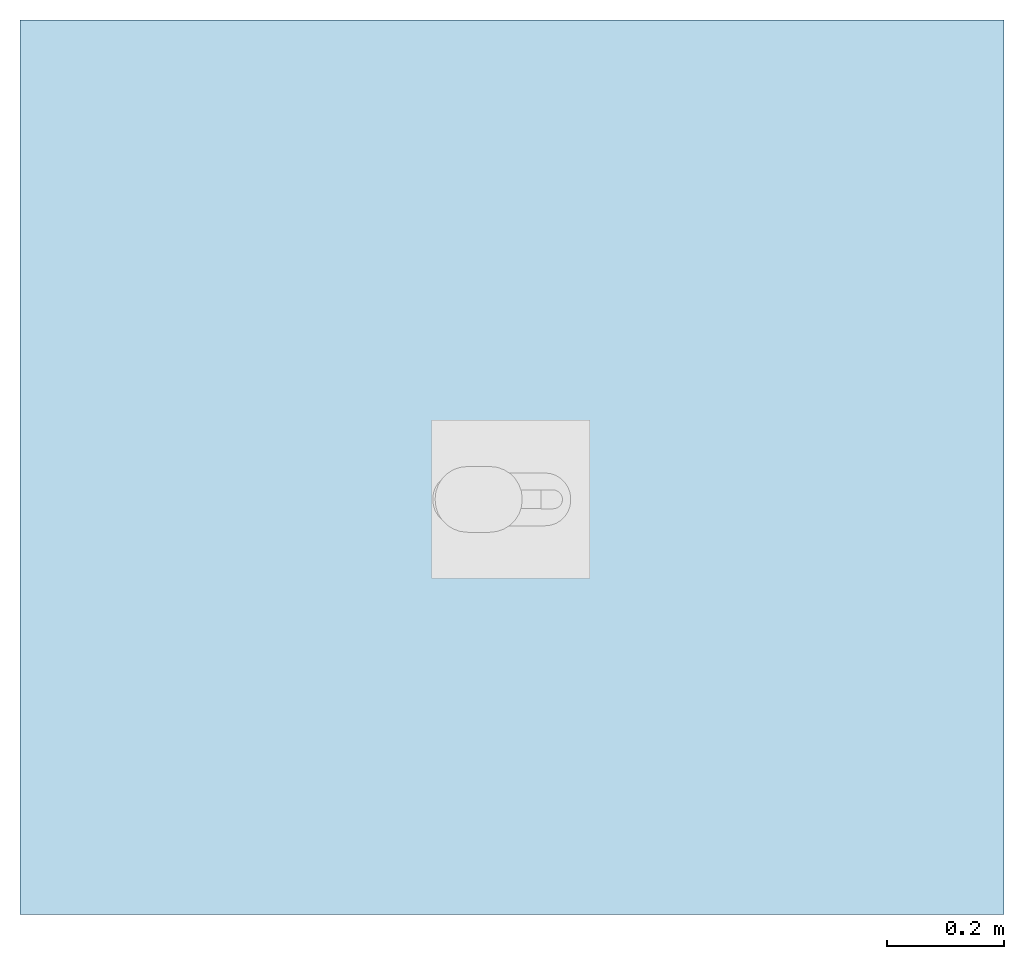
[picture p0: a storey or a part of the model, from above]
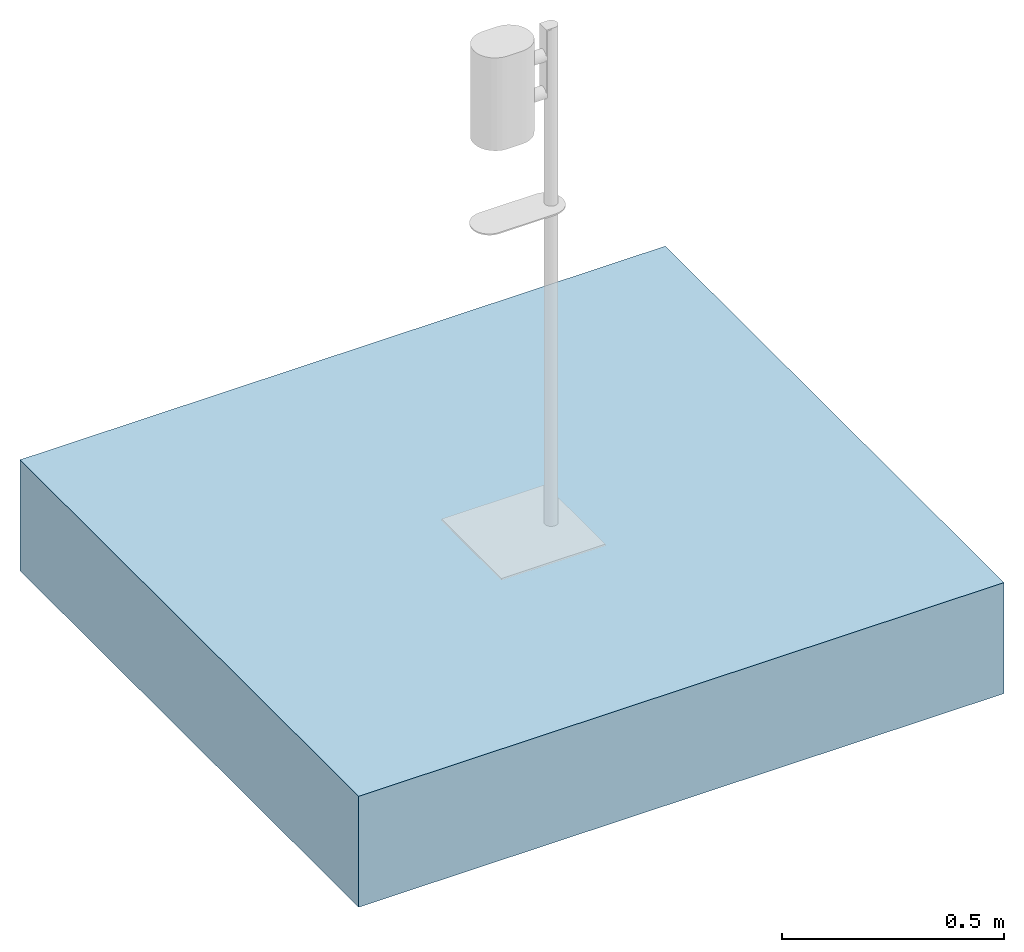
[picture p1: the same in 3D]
Properties of the parts of a building model (IFC2X3)

# File
Description: ViewDefinition [CoordinationView_V2.0]
File name: Project Number
Time: 2023-10-10T10:04:15
Written by: The EXPRESS Data Manager Version 5.02.0100.07 : 28 Aug 2013
Made in: 22.0.2.392 - Exporter 22.0.2.392 - Alternate UI 22.0.2.392
Comment: STEP Physical File produced by: The EXPRESS Data Manager Version 5.02.0100.07 : 28 Aug 2013 * Module: EDMstepFileFactory/EDMstandAlone * Creation date: Tue Oct 10 10:04:15 2023 * Host: DLI-L5jdgnbTSD7 * Database: C:\Users\gba\AppData\Local\Temp\a57e189d-fd9b-4c8a-a0b1-182171568960\53ef2b23-9491-47d2-8210-e2974fee0a87\ifc * Database version: 5507 * Database creation date: Tue Oct 10 10:04:10 2023 * Schema: IFC2X3 * Model: DataRepository.ifc * Model creation date: Tue Oct 10 10:04:11 2023 * Header model: DataRepository.ifc_HeaderModel * Header model creation date: Tue Oct 10 10:04:11 2023 * EDMuser: sdai-user * EDMgroup: sdai-group * License ID and type: 5605 : Permanent license. Expiry date: * EDMstepFileFactory options: 020000

# IfcProject, Project Number
LongName: Project Name; Phase: Project Status

# IfcSite, Default
RefLatitude: 42, 21, 31, 181945; RefLongitude: -71, -3, -24, -263305; RefElevation: 0 ft
Pset_ProductRequirements - Category: Project Information

# IfcBuilding
Pset_BuildingCommon - NumberOfStoreys: 1
Pset_ProductRequirements - Category: Project Information

# IfcBuildingStorey: Level:1/4" Head, First Floor
LongName: First Floor; Elevation: 0 ft
Pset_ProductRequirements - Name: First Floor; Category: Levels
Pset_AirSideSystemInformation - Name: First Floor

# IfcDoor: 14704602040:d_line_Sanitary_WallMountedPanels_TouchlessDisinfectantDispenser_Free-Standing, 14704602040:d_line_Sanitary_WallMountedPanels_TouchlessDisinfectantDispenser_Free-Standing:565435
In: First Floor
Type - ParameterTakesPrecedence: no; Sizeable: no; Material: <Unnamed> (9)
Type - Pset_DoorCommon - IsExternal: no
Type - Pset_ElementShading - Color: n/a
Type - Pset_ManufacturerTypeInformation - ModelReference: 45-35-72/358; Manufacturer: info@dline.com
Type - Pset_ProductRequirements - Name: d_line_Sanitary_WallMountedPanels_TouchlessDisinfectantDispenser_Free-Standing; Category: Doors
OverallHeight: 4.50951 ft; OverallWidth: 0.885827 ft
Pset_DoorCommon - Reference: d_line_Sanitary_WallMountedPanels_TouchlessDisinfectantDispenser_Free-Standing
Pset_ManufacturerOccurrence - BarCode: n/a; SerialNumber: n/a
Pset_PrecastConcreteElementGeneral - SerialNumber: n/a
Pset_QuantityTakeOff - Reference: d_line_Sanitary_WallMountedPanels_TouchlessDisinfectantDispenser_Free-Standing

# IfcSlab: Floor:Generic - 12", Floor:Generic - 12":564379
In: First Floor
Type - PredefinedType: FLOOR; Material: Default Floor 1 ft
Type - Pset_ElementShading - Roughness: 1 ft
Type - Pset_ProductRequirements - Category: Floors
Type - Pset_SlabCommon - IsExternal: no
Classification: B1010 Floor Construction (Uniformat)
Pset_QuantityTakeOff - Reference: Generic - 12"; sets with these values: 2
Pset_SlabCommon - Reference: Generic - 12"; LoadBearing: no; PitchAngle: 0 deg
